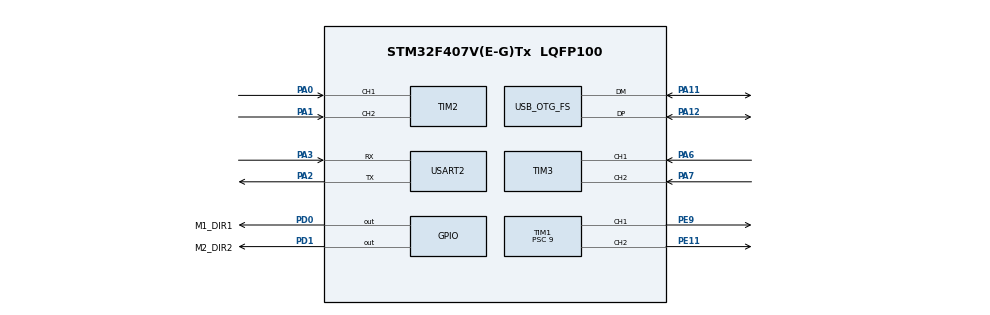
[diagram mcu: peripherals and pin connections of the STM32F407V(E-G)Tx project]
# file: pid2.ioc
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Mcu.Family=STM32F4
Mcu.Name=STM32F407V(E-G)Tx
Mcu.Package=LQFP100
NVIC.OTG_FS_IRQn=true\:0\:0\:false\:false\:true\:false\:true\:true
NVIC.PriorityGroup=NVIC_PRIORITYGROUP_4
PA0-WKUP.Signal=S_TIM2_CH1_ETR
PA1.Signal=S_TIM2_CH2
PA11.Mode=Device_Only
PA11.Signal=USB_OTG_FS_DM
PA12.Mode=Device_Only
PA12.Signal=USB_OTG_FS_DP
PA2.Mode=Asynchronous
PA2.Signal=USART2_TX
PA3.Mode=Asynchronous
PA3.Signal=USART2_RX
PA6.Signal=S_TIM3_CH1
PA7.Signal=S_TIM3_CH2
PD0.GPIO_Label=M1_DIR1
PD0.Signal=GPIO_Output
PD1.GPIO_Label=M2_DIR2
PD1.Signal=GPIO_Output
PE11.Signal=S_TIM1_CH2
PE9.Signal=S_TIM1_CH1
PH0-OSC_IN.Mode=HSE-External-Oscillator
PH0-OSC_IN.Signal=RCC_OSC_IN
PH1-OSC_OUT.Mode=HSE-External-Oscillator
PH1-OSC_OUT.Signal=RCC_OSC_OUT
ProjectManager.HeapSize=0x200
ProjectManager.StackSize=0x400
ProjectManager.TargetToolchain=STM32CubeIDE
RCC.48MHZClocksFreq_Value=48000000
RCC.AHBFreq_Value=168000000
RCC.APB1CLKDivider=RCC_HCLK_DIV4
RCC.APB1Freq_Value=42000000
RCC.APB1TimFreq_Value=84000000
RCC.APB2CLKDivider=RCC_HCLK_DIV2
RCC.APB2Freq_Value=84000000
RCC.APB2TimFreq_Value=168000000
RCC.CortexFreq_Value=168000000
RCC.HCLKFreq_Value=168000000
RCC.HSE_VALUE=25000000
RCC.HSI_VALUE=16000000
RCC.LSE_VALUE=32768
RCC.PLLM=25
RCC.PLLN=336
RCC.PLLQ=7
RCC.SYSCLKFreq_VALUE=168000000
RCC.SYSCLKSource=RCC_SYSCLKSOURCE_PLLCLK
RCC.VCOOutputFreq_Value=336000000
SH.S_TIM1_CH1.0=TIM1_CH1,PWM Generation1 CH1
SH.S_TIM1_CH2.0=TIM1_CH2,PWM Generation2 CH2
SH.S_TIM2_CH1_ETR.0=TIM2_CH1,Encoder_Interface
SH.S_TIM2_CH2.0=TIM2_CH2,Encoder_Interface
SH.S_TIM3_CH1.0=TIM3_CH1,Encoder_Interface
SH.S_TIM3_CH2.0=TIM3_CH2,Encoder_Interface
TIM1.Channel-PWM\ Generation1\ CH1=TIM_CHANNEL_1
TIM1.Channel-PWM\ Generation2\ CH2=TIM_CHANNEL_2
TIM1.Prescaler=9
USART2.VirtualMode=VM_ASYNC
USB_DEVICE.CLASS_NAME_FS=CDC
USB_DEVICE.VirtualMode-CDC_FS=Cdc
USB_DEVICE.VirtualModeFS=Cdc_FS
USB_OTG_FS.VirtualMode=Device_Only
VP_USB_DEVICE_VS_USB_DEVICE_CDC_FS.Mode=CDC_FS
board=custom

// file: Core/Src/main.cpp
/* USER CODE BEGIN Header */
/**
  ******************************************************************************
  * @file           : main.c
  * @brief          : Main program body
  ******************************************************************************
  * @attention
  *
  * Copyright (c) 2026 STMicroelectronics.
  * All rights reserved.
  *
  * This software is licensed under terms that can be found in the LICENSE file
  * in the root directory of this software component.
  * If no LICENSE file comes with this software, it is provided AS-IS.
  *
  ******************************************************************************
  */
/* USER CODE END Header */
#include "main.h"
#include "pid_v1.h"
#include <stdio.h>
#include <stdlib.h>
#include <string.h>
#include "usb_device.h"
#include "usbd_cdc_if.h"

TIM_HandleTypeDef htim1;
TIM_HandleTypeDef htim2;
TIM_HandleTypeDef htim3;

UART_HandleTypeDef huart2;

void SystemClock_Config(void);
static void MX_GPIO_Init(void);
static void MX_TIM1_Init(void);
static void MX_TIM2_Init(void);
static void MX_TIM3_Init(void);
static void MX_USART2_UART_Init(void);

/* USER CODE BEGIN 0 */
#define PPR 400.0            // Your encoder pulses per revolution
#define SAMPLE_TIME 100      // 100ms calculation interval
#define TARGET_RPM 150.0     // Set your desired speed in RPM here

// --- EXTERNAL HANDLES (Generated by CubeMX) ---
extern TIM_HandleTypeDef htim1; // PWM Timer
extern TIM_HandleTypeDef htim2; // Encoder 1 Timer (32-bit)
extern TIM_HandleTypeDef htim3; // Encoder 2 Timer (16-bit)
extern UART_HandleTypeDef huart2; // Change to your active UART for debugging

// --- PID & ENCODER VARIABLES ---
double Setpoint1, Input1, Output1;
double Setpoint2, Input2, Output2;

double Kp = 1.0, Ki = 1.0, Kd = 0.0;

PID PID1(&Input1, &Output1, &Setpoint1, Kp, Ki, Kd, PID::DIRECT);
PID PID2(&Input2, &Output2, &Setpoint2, Kp, Ki, Kd, PID::DIRECT);

uint32_t lastTime = 0;
uint32_t lastEnc1 = 0; // TIM2 is 32-bit
uint16_t lastEnc2 = 0; // TIM3 is 16-bit

// Helper function for Serial Debugging via UART
void Serial_Print(const char* buf) {
    HAL_UART_Transmit(&huart2, (uint8_t*)buf, strlen(buf), 100);
}
/* USER CODE END 0 */

int main(void)
{

  /* MCU Configuration--------------------------------------------------------*/

  /* Reset of all peripherals, Initializes the Flash interface and the Systick. */
  HAL_Init();

  /* Configure the system clock */
  SystemClock_Config();

  /* Initialize all configured peripherals */
  MX_GPIO_Init();
  MX_TIM1_Init();
  MX_TIM2_Init();
  MX_TIM3_Init();
  MX_USART2_UART_Init();
  /* USER CODE BEGIN 2 */
  // 1. Start Encoders
    HAL_TIM_Encoder_Start(&htim2, TIM_CHANNEL_ALL);
    HAL_TIM_Encoder_Start(&htim3, TIM_CHANNEL_ALL);

    // 2. Start PWM for Cytron AN1 and AN2
    HAL_TIM_PWM_Start(&htim1, TIM_CHANNEL_1);
    HAL_TIM_PWM_Start(&htim1, TIM_CHANNEL_2);

    // 3. Setup Target RPM
    Setpoint1 = TARGET_RPM;
    Setpoint2 = TARGET_RPM;

    // 4. Setup PID Configuration
    PID1.SetMode(PID::AUTOMATIC);
    PID2.SetMode(PID::AUTOMATIC);

    // STM32 PWM Output limits set to 0-1000 (Based on ARR=999 in CubeMX)
    PID1.SetOutputLimits(0, 1000);
    PID2.SetOutputLimits(0, 1000);

    PID1.SetSampleTime(SAMPLE_TIME);
    PID2.SetSampleTime(SAMPLE_TIME);
  /* USER CODE END 2 */

  /* Infinite loop */
  while (1)
  {
	  uint32_t currentTime = HAL_GetTick(); // STM32 equivalent of millis()

	      if (currentTime - lastTime >= SAMPLE_TIME) {

	          // 1. Read Raw Pulses from Hardware Timers
	          // F407: TIM2 is 32-bit, TIM3 is 16-bit
	          uint32_t currentEnc1 = __HAL_TIM_GET_COUNTER(&htim2);
	          uint16_t currentEnc2 = __HAL_TIM_GET_COUNTER(&htim3);

	          // Calculate delta (unsigned math naturally handles timer rollovers)
	          int32_t pulses1 = abs((int32_t)(currentEnc1 - lastEnc1));
	          int32_t pulses2 = abs((int16_t)(currentEnc2 - lastEnc2));

	          // 2. Convert Pulses to RPM
	          Input1 = (((double)pulses1) / PPR) * (60000.0 / SAMPLE_TIME);
	          Input2 = (((double)pulses2) / PPR) * (60000.0 / SAMPLE_TIME);

	          // 3. Compute PID Calculations
	          PID1.Compute(currentTime);
	          PID2.Compute(currentTime);

	          // 4. Drive Cytron MDDS Motors

	          // Motor 1 (Left)
	          HAL_GPIO_WritePin(GPIOD, GPIO_PIN_0, GPIO_PIN_SET); // DIG1 Forward
	          __HAL_TIM_SET_COMPARE(&htim1, TIM_CHANNEL_1, (uint32_t)Output1); // AN1 Speed

	          // Motor 2 (Right)
	          HAL_GPIO_WritePin(GPIOD, GPIO_PIN_1, GPIO_PIN_SET); // DIG2 Forward
	          __HAL_TIM_SET_COMPARE(&htim1, TIM_CHANNEL_2, (uint32_t)Output2); // AN2 Speed

	          // 5. Debugging Output (Format: Target | M1_RPM | M1_PWM | M2_RPM | M2_PWM)
	          char msg[128];
	          snprintf(msg, sizeof(msg), "T:%.1f | RPM1:%.1f PWM1:%.0f | RPM2:%.1f PWM2:%.0f\r\n",Setpoint1, Input1, Output1, Input2, Output2);
	          Serial_Print(msg);

	          // 6. Save current state for next loop
	          lastEnc1 = currentEnc1;
	          lastEnc2 = currentEnc2;
	          lastTime = currentTime;
	      }
  }
}

void SystemClock_Config(void)
{
  RCC_OscInitTypeDef RCC_OscInitStruct = {0};
  RCC_ClkInitTypeDef RCC_ClkInitStruct = {0};

  /** Configure the main internal regulator output voltage
  */
  __HAL_RCC_PWR_CLK_ENABLE();
  __HAL_PWR_VOLTAGESCALING_CONFIG(PWR_REGULATOR_VOLTAGE_SCALE1);

  /** Initializes the RCC Oscillators according to the specified parameters
  * in the RCC_OscInitTypeDef structure.
  */
  RCC_OscInitStruct.OscillatorType = RCC_OSCILLATORTYPE_HSI;
  RCC_OscInitStruct.HSIState = RCC_HSI_ON;
  RCC_OscInitStruct.HSICalibrationValue = RCC_HSICALIBRATION_DEFAULT;
  RCC_OscInitStruct.PLL.PLLState = RCC_PLL_NONE;
  if (HAL_RCC_OscConfig(&RCC_OscInitStruct) != HAL_OK)
  {
    Error_Handler();
  }

  /** Initializes the CPU, AHB and APB buses clocks
  */
  RCC_ClkInitStruct.ClockType = RCC_CLOCKTYPE_HCLK|RCC_CLOCKTYPE_SYSCLK
                              |RCC_CLOCKTYPE_PCLK1|RCC_CLOCKTYPE_PCLK2;
  RCC_ClkInitStruct.SYSCLKSource = RCC_SYSCLKSOURCE_HSI;
  RCC_ClkInitStruct.AHBCLKDivider = RCC_SYSCLK_DIV1;
  RCC_ClkInitStruct.APB1CLKDivider = RCC_HCLK_DIV1;
  RCC_ClkInitStruct.APB2CLKDivider = RCC_HCLK_DIV1;

  if (HAL_RCC_ClockConfig(&RCC_ClkInitStruct, FLASH_LATENCY_0) != HAL_OK)
  {
    Error_Handler();
  }
}

static void MX_TIM1_Init(void)
{

  TIM_MasterConfigTypeDef sMasterConfig = {0};
  TIM_OC_InitTypeDef sConfigOC = {0};
  TIM_BreakDeadTimeConfigTypeDef sBreakDeadTimeConfig = {0};

  htim1.Instance = TIM1;
  htim1.Init.Prescaler = 9;
  htim1.Init.CounterMode = TIM_COUNTERMODE_UP;
  htim1.Init.Period = 65535;
  htim1.Init.ClockDivision = TIM_CLOCKDIVISION_DIV1;
  htim1.Init.RepetitionCounter = 0;
  htim1.Init.AutoReloadPreload = TIM_AUTORELOAD_PRELOAD_DISABLE;
  if (HAL_TIM_PWM_Init(&htim1) != HAL_OK)
  {
    Error_Handler();
  }
  sMasterConfig.MasterOutputTrigger = TIM_TRGO_RESET;
  sMasterConfig.MasterSlaveMode = TIM_MASTERSLAVEMODE_DISABLE;
  if (HAL_TIMEx_MasterConfigSynchronization(&htim1, &sMasterConfig) != HAL_OK)
  {
    Error_Handler();
  }
  sConfigOC.OCMode = TIM_OCMODE_PWM1;
  sConfigOC.Pulse = 0;
  sConfigOC.OCPolarity = TIM_OCPOLARITY_HIGH;
  sConfigOC.OCNPolarity = TIM_OCNPOLARITY_HIGH;
  sConfigOC.OCFastMode = TIM_OCFAST_DISABLE;
  sConfigOC.OCIdleState = TIM_OCIDLESTATE_RESET;
  sConfigOC.OCNIdleState = TIM_OCNIDLESTATE_RESET;
  if (HAL_TIM_PWM_ConfigChannel(&htim1, &sConfigOC, TIM_CHANNEL_1) != HAL_OK)
  {
    Error_Handler();
  }
  if (HAL_TIM_PWM_ConfigChannel(&htim1, &sConfigOC, TIM_CHANNEL_2) != HAL_OK)
  {
    Error_Handler();
  }
  sBreakDeadTimeConfig.OffStateRunMode = TIM_OSSR_DISABLE;
  sBreakDeadTimeConfig.OffStateIDLEMode = TIM_OSSI_DISABLE;
  sBreakDeadTimeConfig.LockLevel = TIM_LOCKLEVEL_OFF;
  sBreakDeadTimeConfig.DeadTime = 0;
  sBreakDeadTimeConfig.BreakState = TIM_BREAK_DISABLE;
  sBreakDeadTimeConfig.BreakPolarity = TIM_BREAKPOLARITY_HIGH;
  sBreakDeadTimeConfig.AutomaticOutput = TIM_AUTOMATICOUTPUT_DISABLE;
  if (HAL_TIMEx_ConfigBreakDeadTime(&htim1, &sBreakDeadTimeConfig) != HAL_OK)
  {
    Error_Handler();
  }
  HAL_TIM_MspPostInit(&htim1);

}

static void MX_TIM2_Init(void)
{

  TIM_Encoder_InitTypeDef sConfig = {0};
  TIM_MasterConfigTypeDef sMasterConfig = {0};

  htim2.Instance = TIM2;
  htim2.Init.Prescaler = 0;
  htim2.Init.CounterMode = TIM_COUNTERMODE_UP;
  htim2.Init.Period = 4294967295;
  htim2.Init.ClockDivision = TIM_CLOCKDIVISION_DIV1;
  htim2.Init.AutoReloadPreload = TIM_AUTORELOAD_PRELOAD_DISABLE;
  sConfig.EncoderMode = TIM_ENCODERMODE_TI1;
  sConfig.IC1Polarity = TIM_ICPOLARITY_RISING;
  sConfig.IC1Selection = TIM_ICSELECTION_DIRECTTI;
  sConfig.IC1Prescaler = TIM_ICPSC_DIV1;
  sConfig.IC1Filter = 0;
  sConfig.IC2Polarity = TIM_ICPOLARITY_RISING;
  sConfig.IC2Selection = TIM_ICSELECTION_DIRECTTI;
  sConfig.IC2Prescaler = TIM_ICPSC_DIV1;
  sConfig.IC2Filter = 0;
  if (HAL_TIM_Encoder_Init(&htim2, &sConfig) != HAL_OK)
  {
    Error_Handler();
  }
  sMasterConfig.MasterOutputTrigger = TIM_TRGO_RESET;
  sMasterConfig.MasterSlaveMode = TIM_MASTERSLAVEMODE_DISABLE;
  if (HAL_TIMEx_MasterConfigSynchronization(&htim2, &sMasterConfig) != HAL_OK)
  {
    Error_Handler();
  }

}

static void MX_TIM3_Init(void)
{

  TIM_Encoder_InitTypeDef sConfig = {0};
  TIM_MasterConfigTypeDef sMasterConfig = {0};

  htim3.Instance = TIM3;
  htim3.Init.Prescaler = 0;
  htim3.Init.CounterMode = TIM_COUNTERMODE_UP;
  htim3.Init.Period = 65535;
  htim3.Init.ClockDivision = TIM_CLOCKDIVISION_DIV1;
  htim3.Init.AutoReloadPreload = TIM_AUTORELOAD_PRELOAD_DISABLE;
  sConfig.EncoderMode = TIM_ENCODERMODE_TI1;
  sConfig.IC1Polarity = TIM_ICPOLARITY_RISING;
  sConfig.IC1Selection = TIM_ICSELECTION_DIRECTTI;
  sConfig.IC1Prescaler = TIM_ICPSC_DIV1;
  sConfig.IC1Filter = 0;
  sConfig.IC2Polarity = TIM_ICPOLARITY_RISING;
  sConfig.IC2Selection = TIM_ICSELECTION_DIRECTTI;
  sConfig.IC2Prescaler = TIM_ICPSC_DIV1;
  sConfig.IC2Filter = 0;
  if (HAL_TIM_Encoder_Init(&htim3, &sConfig) != HAL_OK)
  {
    Error_Handler();
  }
  sMasterConfig.MasterOutputTrigger = TIM_TRGO_RESET;
  sMasterConfig.MasterSlaveMode = TIM_MASTERSLAVEMODE_DISABLE;
  if (HAL_TIMEx_MasterConfigSynchronization(&htim3, &sMasterConfig) != HAL_OK)
  {
    Error_Handler();
  }

}

static void MX_USART2_UART_Init(void)
{

  huart2.Instance = USART2;
  huart2.Init.BaudRate = 115200;
  huart2.Init.WordLength = UART_WORDLENGTH_8B;
  huart2.Init.StopBits = UART_STOPBITS_1;
  huart2.Init.Parity = UART_PARITY_NONE;
  huart2.Init.Mode = UART_MODE_TX_RX;
  huart2.Init.HwFlowCtl = UART_HWCONTROL_NONE;
  huart2.Init.OverSampling = UART_OVERSAMPLING_16;
  if (HAL_UART_Init(&huart2) != HAL_OK)
  {
    Error_Handler();
  }

}

static void MX_GPIO_Init(void)
{
  GPIO_InitTypeDef GPIO_InitStruct = {0};

  /* GPIO Ports Clock Enable */
  __HAL_RCC_GPIOH_CLK_ENABLE();
  __HAL_RCC_GPIOA_CLK_ENABLE();
  __HAL_RCC_GPIOE_CLK_ENABLE();
  __HAL_RCC_GPIOD_CLK_ENABLE();

  /*Configure GPIO pin Output Level */
  HAL_GPIO_WritePin(GPIOD, M1_DIR1_Pin|M2_DIR2_Pin, GPIO_PIN_RESET);

  /*Configure GPIO pins : M1_DIR1_Pin M2_DIR2_Pin */
  GPIO_InitStruct.Pin = M1_DIR1_Pin|M2_DIR2_Pin;
  GPIO_InitStruct.Mode = GPIO_MODE_OUTPUT_PP;
  GPIO_InitStruct.Pull = GPIO_NOPULL;
  GPIO_InitStruct.Speed = GPIO_SPEED_FREQ_LOW;
  HAL_GPIO_Init(GPIOD, &GPIO_InitStruct);

}

/* USER CODE BEGIN 4 */
int _write(int file, char *ptr, int len) {
    uint8_t result = CDC_Transmit_FS((uint8_t*)ptr, len);

    // Wait for the transmission to complete to avoid overlapping buffers
    // Use a small delay or check the busy status of the CDC interface

    return (result == USBD_OK) ? len : 0;
}
/* USER CODE END 4 */

void Error_Handler(void)
{
  __disable_irq();
  while (1)
  {
  }
}
